# Generated by FakeRAM 2.0
VERSION 5.7 ;
BUSBITCHARS "[]" ;
PROPERTYDEFINITIONS
  MACRO width INTEGER ;
  MACRO depth INTEGER ;
  MACRO banks INTEGER ;
END PROPERTYDEFINITIONS
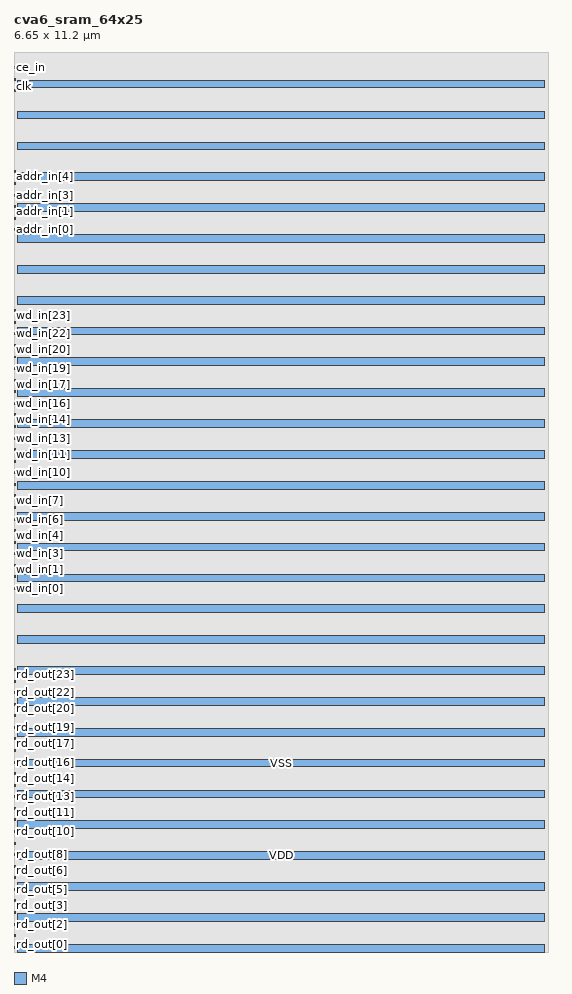
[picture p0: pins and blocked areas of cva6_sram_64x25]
MACRO cva6_sram_64x25
  PROPERTY width 25 ;
  PROPERTY depth 64 ;
  PROPERTY banks 1 ;
  FOREIGN cva6_sram_64x25 0 0 ;
  SYMMETRY X Y R90 ;
  SIZE 6.6500 BY 11.2000 ;
  CLASS BLOCK ;
  PIN rd_out[0]
    DIRECTION OUTPUT ;
    USE SIGNAL ;
    PORT
      LAYER M4 ;
      RECT 0.00000 0.04800 0.02400 0.07200 ;
    END
  END rd_out[0]
  PIN rd_out[1]
    DIRECTION OUTPUT ;
    USE SIGNAL ;
    PORT
      LAYER M4 ;
      RECT 0.00000 0.19200 0.02400 0.21600 ;
    END
  END rd_out[1]
  PIN rd_out[2]
    DIRECTION OUTPUT ;
    USE SIGNAL ;
    PORT
      LAYER M4 ;
      RECT 0.00000 0.33600 0.02400 0.36000 ;
    END
  END rd_out[2]
  PIN rd_out[3]
    DIRECTION OUTPUT ;
    USE SIGNAL ;
    PORT
      LAYER M4 ;
      RECT 0.00000 0.48000 0.02400 0.50400 ;
    END
  END rd_out[3]
  PIN rd_out[4]
    DIRECTION OUTPUT ;
    USE SIGNAL ;
    PORT
      LAYER M4 ;
      RECT 0.00000 0.62400 0.02400 0.64800 ;
    END
  END rd_out[4]
  PIN rd_out[5]
    DIRECTION OUTPUT ;
    USE SIGNAL ;
    PORT
      LAYER M4 ;
      RECT 0.00000 0.76800 0.02400 0.79200 ;
    END
  END rd_out[5]
  PIN rd_out[6]
    DIRECTION OUTPUT ;
    USE SIGNAL ;
    PORT
      LAYER M4 ;
      RECT 0.00000 0.91200 0.02400 0.93600 ;
    END
  END rd_out[6]
  PIN rd_out[7]
    DIRECTION OUTPUT ;
    USE SIGNAL ;
    PORT
      LAYER M4 ;
      RECT 0.00000 1.05600 0.02400 1.08000 ;
    END
  END rd_out[7]
  PIN rd_out[8]
    DIRECTION OUTPUT ;
    USE SIGNAL ;
    PORT
      LAYER M4 ;
      RECT 0.00000 1.20000 0.02400 1.22400 ;
    END
  END rd_out[8]
  PIN rd_out[9]
    DIRECTION OUTPUT ;
    USE SIGNAL ;
    PORT
      LAYER M4 ;
      RECT 0.00000 1.34400 0.02400 1.36800 ;
    END
  END rd_out[9]
  PIN rd_out[10]
    DIRECTION OUTPUT ;
    USE SIGNAL ;
    PORT
      LAYER M4 ;
      RECT 0.00000 1.48800 0.02400 1.51200 ;
    END
  END rd_out[10]
  PIN rd_out[11]
    DIRECTION OUTPUT ;
    USE SIGNAL ;
    PORT
      LAYER M4 ;
      RECT 0.00000 1.63200 0.02400 1.65600 ;
    END
  END rd_out[11]
  PIN rd_out[12]
    DIRECTION OUTPUT ;
    USE SIGNAL ;
    PORT
      LAYER M4 ;
      RECT 0.00000 1.77600 0.02400 1.80000 ;
    END
  END rd_out[12]
  PIN rd_out[13]
    DIRECTION OUTPUT ;
    USE SIGNAL ;
    PORT
      LAYER M4 ;
      RECT 0.00000 1.92000 0.02400 1.94400 ;
    END
  END rd_out[13]
  PIN rd_out[14]
    DIRECTION OUTPUT ;
    USE SIGNAL ;
    PORT
      LAYER M4 ;
      RECT 0.00000 2.06400 0.02400 2.08800 ;
    END
  END rd_out[14]
  PIN rd_out[15]
    DIRECTION OUTPUT ;
    USE SIGNAL ;
    PORT
      LAYER M4 ;
      RECT 0.00000 2.20800 0.02400 2.23200 ;
    END
  END rd_out[15]
  PIN rd_out[16]
    DIRECTION OUTPUT ;
    USE SIGNAL ;
    PORT
      LAYER M4 ;
      RECT 0.00000 2.35200 0.02400 2.37600 ;
    END
  END rd_out[16]
  PIN rd_out[17]
    DIRECTION OUTPUT ;
    USE SIGNAL ;
    PORT
      LAYER M4 ;
      RECT 0.00000 2.49600 0.02400 2.52000 ;
    END
  END rd_out[17]
  PIN rd_out[18]
    DIRECTION OUTPUT ;
    USE SIGNAL ;
    PORT
      LAYER M4 ;
      RECT 0.00000 2.64000 0.02400 2.66400 ;
    END
  END rd_out[18]
  PIN rd_out[19]
    DIRECTION OUTPUT ;
    USE SIGNAL ;
    PORT
      LAYER M4 ;
      RECT 0.00000 2.78400 0.02400 2.80800 ;
    END
  END rd_out[19]
  PIN rd_out[20]
    DIRECTION OUTPUT ;
    USE SIGNAL ;
    PORT
      LAYER M4 ;
      RECT 0.00000 2.92800 0.02400 2.95200 ;
    END
  END rd_out[20]
  PIN rd_out[21]
    DIRECTION OUTPUT ;
    USE SIGNAL ;
    PORT
      LAYER M4 ;
      RECT 0.00000 3.07200 0.02400 3.09600 ;
    END
  END rd_out[21]
  PIN rd_out[22]
    DIRECTION OUTPUT ;
    USE SIGNAL ;
    PORT
      LAYER M4 ;
      RECT 0.00000 3.21600 0.02400 3.24000 ;
    END
  END rd_out[22]
  PIN rd_out[23]
    DIRECTION OUTPUT ;
    USE SIGNAL ;
    PORT
      LAYER M4 ;
      RECT 0.00000 3.36000 0.02400 3.38400 ;
    END
  END rd_out[23]
  PIN rd_out[24]
    DIRECTION OUTPUT ;
    USE SIGNAL ;
    PORT
      LAYER M4 ;
      RECT 0.00000 3.50400 0.02400 3.52800 ;
    END
  END rd_out[24]
  PIN wd_in[0]
    DIRECTION INPUT ;
    USE SIGNAL ;
    PORT
      LAYER M4 ;
      RECT 0.00000 4.51200 0.02400 4.53600 ;
    END
  END wd_in[0]
  PIN wd_in[1]
    DIRECTION INPUT ;
    USE SIGNAL ;
    PORT
      LAYER M4 ;
      RECT 0.00000 4.65600 0.02400 4.68000 ;
    END
  END wd_in[1]
  PIN wd_in[2]
    DIRECTION INPUT ;
    USE SIGNAL ;
    PORT
      LAYER M4 ;
      RECT 0.00000 4.80000 0.02400 4.82400 ;
    END
  END wd_in[2]
  PIN wd_in[3]
    DIRECTION INPUT ;
    USE SIGNAL ;
    PORT
      LAYER M4 ;
      RECT 0.00000 4.94400 0.02400 4.96800 ;
    END
  END wd_in[3]
  PIN wd_in[4]
    DIRECTION INPUT ;
    USE SIGNAL ;
    PORT
      LAYER M4 ;
      RECT 0.00000 5.08800 0.02400 5.11200 ;
    END
  END wd_in[4]
  PIN wd_in[5]
    DIRECTION INPUT ;
    USE SIGNAL ;
    PORT
      LAYER M4 ;
      RECT 0.00000 5.23200 0.02400 5.25600 ;
    END
  END wd_in[5]
  PIN wd_in[6]
    DIRECTION INPUT ;
    USE SIGNAL ;
    PORT
      LAYER M4 ;
      RECT 0.00000 5.37600 0.02400 5.40000 ;
    END
  END wd_in[6]
  PIN wd_in[7]
    DIRECTION INPUT ;
    USE SIGNAL ;
    PORT
      LAYER M4 ;
      RECT 0.00000 5.52000 0.02400 5.54400 ;
    END
  END wd_in[7]
  PIN wd_in[8]
    DIRECTION INPUT ;
    USE SIGNAL ;
    PORT
      LAYER M4 ;
      RECT 0.00000 5.66400 0.02400 5.68800 ;
    END
  END wd_in[8]
  PIN wd_in[9]
    DIRECTION INPUT ;
    USE SIGNAL ;
    PORT
      LAYER M4 ;
      RECT 0.00000 5.80800 0.02400 5.83200 ;
    END
  END wd_in[9]
  PIN wd_in[10]
    DIRECTION INPUT ;
    USE SIGNAL ;
    PORT
      LAYER M4 ;
      RECT 0.00000 5.95200 0.02400 5.97600 ;
    END
  END wd_in[10]
  PIN wd_in[11]
    DIRECTION INPUT ;
    USE SIGNAL ;
    PORT
      LAYER M4 ;
      RECT 0.00000 6.09600 0.02400 6.12000 ;
    END
  END wd_in[11]
  PIN wd_in[12]
    DIRECTION INPUT ;
    USE SIGNAL ;
    PORT
      LAYER M4 ;
      RECT 0.00000 6.24000 0.02400 6.26400 ;
    END
  END wd_in[12]
  PIN wd_in[13]
    DIRECTION INPUT ;
    USE SIGNAL ;
    PORT
      LAYER M4 ;
      RECT 0.00000 6.38400 0.02400 6.40800 ;
    END
  END wd_in[13]
  PIN wd_in[14]
    DIRECTION INPUT ;
    USE SIGNAL ;
    PORT
      LAYER M4 ;
      RECT 0.00000 6.52800 0.02400 6.55200 ;
    END
  END wd_in[14]
  PIN wd_in[15]
    DIRECTION INPUT ;
    USE SIGNAL ;
    PORT
      LAYER M4 ;
      RECT 0.00000 6.67200 0.02400 6.69600 ;
    END
  END wd_in[15]
  PIN wd_in[16]
    DIRECTION INPUT ;
    USE SIGNAL ;
    PORT
      LAYER M4 ;
      RECT 0.00000 6.81600 0.02400 6.84000 ;
    END
  END wd_in[16]
  PIN wd_in[17]
    DIRECTION INPUT ;
    USE SIGNAL ;
    PORT
      LAYER M4 ;
      RECT 0.00000 6.96000 0.02400 6.98400 ;
    END
  END wd_in[17]
  PIN wd_in[18]
    DIRECTION INPUT ;
    USE SIGNAL ;
    PORT
      LAYER M4 ;
      RECT 0.00000 7.10400 0.02400 7.12800 ;
    END
  END wd_in[18]
  PIN wd_in[19]
    DIRECTION INPUT ;
    USE SIGNAL ;
    PORT
      LAYER M4 ;
      RECT 0.00000 7.24800 0.02400 7.27200 ;
    END
  END wd_in[19]
  PIN wd_in[20]
    DIRECTION INPUT ;
    USE SIGNAL ;
    PORT
      LAYER M4 ;
      RECT 0.00000 7.39200 0.02400 7.41600 ;
    END
  END wd_in[20]
  PIN wd_in[21]
    DIRECTION INPUT ;
    USE SIGNAL ;
    PORT
      LAYER M4 ;
      RECT 0.00000 7.53600 0.02400 7.56000 ;
    END
  END wd_in[21]
  PIN wd_in[22]
    DIRECTION INPUT ;
    USE SIGNAL ;
    PORT
      LAYER M4 ;
      RECT 0.00000 7.68000 0.02400 7.70400 ;
    END
  END wd_in[22]
  PIN wd_in[23]
    DIRECTION INPUT ;
    USE SIGNAL ;
    PORT
      LAYER M4 ;
      RECT 0.00000 7.82400 0.02400 7.84800 ;
    END
  END wd_in[23]
  PIN wd_in[24]
    DIRECTION INPUT ;
    USE SIGNAL ;
    PORT
      LAYER M4 ;
      RECT 0.00000 7.96800 0.02400 7.99200 ;
    END
  END wd_in[24]
  PIN addr_in[0]
    DIRECTION INPUT ;
    USE SIGNAL ;
    PORT
      LAYER M4 ;
      RECT 0.00000 8.97600 0.02400 9.00000 ;
    END
  END addr_in[0]
  PIN addr_in[1]
    DIRECTION INPUT ;
    USE SIGNAL ;
    PORT
      LAYER M4 ;
      RECT 0.00000 9.12000 0.02400 9.14400 ;
    END
  END addr_in[1]
  PIN addr_in[2]
    DIRECTION INPUT ;
    USE SIGNAL ;
    PORT
      LAYER M4 ;
      RECT 0.00000 9.26400 0.02400 9.28800 ;
    END
  END addr_in[2]
  PIN addr_in[3]
    DIRECTION INPUT ;
    USE SIGNAL ;
    PORT
      LAYER M4 ;
      RECT 0.00000 9.40800 0.02400 9.43200 ;
    END
  END addr_in[3]
  PIN addr_in[4]
    DIRECTION INPUT ;
    USE SIGNAL ;
    PORT
      LAYER M4 ;
      RECT 0.00000 9.55200 0.02400 9.57600 ;
    END
  END addr_in[4]
  PIN addr_in[5]
    DIRECTION INPUT ;
    USE SIGNAL ;
    PORT
      LAYER M4 ;
      RECT 0.00000 9.69600 0.02400 9.72000 ;
    END
  END addr_in[5]
  PIN we_in
    DIRECTION INPUT ;
    USE SIGNAL ;
    PORT
      LAYER M4 ;
      RECT 0.00000 10.70400 0.02400 10.72800 ;
    END
  END we_in
  PIN clk
    DIRECTION INPUT ;
    USE SIGNAL ;
    PORT
      LAYER M4 ;
      RECT 0.00000 10.84800 0.02400 10.87200 ;
    END
  END clk
  PIN ce_in
    DIRECTION INPUT ;
    USE SIGNAL ;
    PORT
      LAYER M4 ;
      RECT 0.00000 10.99200 0.02400 11.01600 ;
    END
  END ce_in
  PIN VDD
    DIRECTION INOUT ;
    USE POWER ;
    PORT
      LAYER M4 ;
      RECT 0.04800 0.38400 6.60200 0.48000 ;
      RECT 0.04800 1.15200 6.60200 1.24800 ;
      RECT 0.04800 1.92000 6.60200 2.01600 ;
      RECT 0.04800 2.68800 6.60200 2.78400 ;
      RECT 0.04800 3.45600 6.60200 3.55200 ;
      RECT 0.04800 4.22400 6.60200 4.32000 ;
      RECT 0.04800 4.99200 6.60200 5.08800 ;
      RECT 0.04800 5.76000 6.60200 5.85600 ;
      RECT 0.04800 6.52800 6.60200 6.62400 ;
      RECT 0.04800 7.29600 6.60200 7.39200 ;
      RECT 0.04800 8.06400 6.60200 8.16000 ;
      RECT 0.04800 8.83200 6.60200 8.92800 ;
      RECT 0.04800 9.60000 6.60200 9.69600 ;
      RECT 0.04800 10.36800 6.60200 10.46400 ;
    END
  END VDD
  PIN VSS
    DIRECTION INOUT ;
    USE GROUND ;
    PORT
      LAYER M4 ;
      RECT 0.04800 0.00000 6.60200 0.09600 ;
      RECT 0.04800 0.76800 6.60200 0.86400 ;
      RECT 0.04800 1.53600 6.60200 1.63200 ;
      RECT 0.04800 2.30400 6.60200 2.40000 ;
      RECT 0.04800 3.07200 6.60200 3.16800 ;
      RECT 0.04800 3.84000 6.60200 3.93600 ;
      RECT 0.04800 4.60800 6.60200 4.70400 ;
      RECT 0.04800 5.37600 6.60200 5.47200 ;
      RECT 0.04800 6.14400 6.60200 6.24000 ;
      RECT 0.04800 6.91200 6.60200 7.00800 ;
      RECT 0.04800 7.68000 6.60200 7.77600 ;
      RECT 0.04800 8.44800 6.60200 8.54400 ;
      RECT 0.04800 9.21600 6.60200 9.31200 ;
      RECT 0.04800 9.98400 6.60200 10.08000 ;
      RECT 0.04800 10.75200 6.60200 10.84800 ;
    END
  END VSS
  OBS
    LAYER M1 ;
    RECT 0 0 6.65000 11.20000 ;
    LAYER M2 ;
    RECT 0 0 6.65000 11.20000 ;
    LAYER M3 ;
    RECT 0 0 6.65000 11.20000 ;
    LAYER M4 ;
    RECT 0 0 6.65000 11.20000 ;
  END
END cva6_sram_64x25

END LIBRARY
